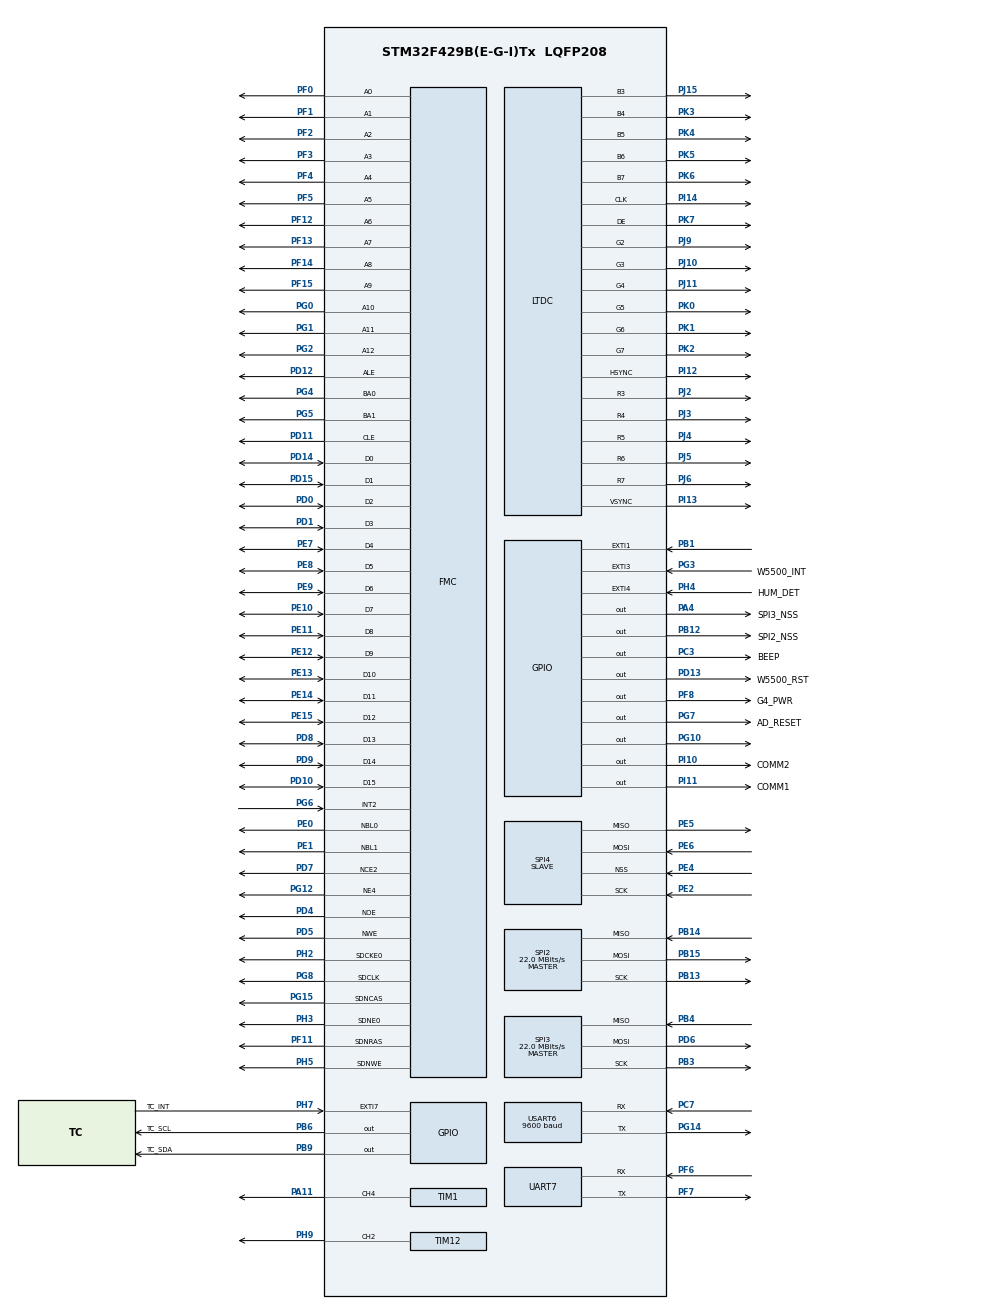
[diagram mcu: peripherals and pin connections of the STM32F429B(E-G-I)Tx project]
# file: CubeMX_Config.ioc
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DMA2D.ColorMode=DMA2D_OUTPUT_RGB565
Dma.MEMTOMEM.0.Direction=DMA_MEMORY_TO_MEMORY
Dma.MEMTOMEM.0.FIFOMode=DMA_FIFOMODE_ENABLE
Dma.MEMTOMEM.0.FIFOThreshold=DMA_FIFO_THRESHOLD_FULL
Dma.MEMTOMEM.0.Instance=DMA2_Stream0
Dma.MEMTOMEM.0.MemBurst=DMA_MBURST_INC8
Dma.MEMTOMEM.0.MemDataAlignment=DMA_MDATAALIGN_HALFWORD
Dma.MEMTOMEM.0.MemInc=DMA_MINC_ENABLE
Dma.MEMTOMEM.0.Mode=DMA_NORMAL
Dma.MEMTOMEM.0.PeriphBurst=DMA_PBURST_INC8
Dma.MEMTOMEM.0.PeriphDataAlignment=DMA_PDATAALIGN_HALFWORD
Dma.MEMTOMEM.0.PeriphInc=DMA_PINC_ENABLE
Dma.MEMTOMEM.0.Priority=DMA_PRIORITY_HIGH
Dma.Request0=MEMTOMEM
Dma.Request1=SPI4_RX
Dma.Request2=SPI4_TX
Dma.SPI4_RX.1.Direction=DMA_PERIPH_TO_MEMORY
Dma.SPI4_RX.1.FIFOMode=DMA_FIFOMODE_ENABLE
Dma.SPI4_RX.1.FIFOThreshold=DMA_FIFO_THRESHOLD_FULL
Dma.SPI4_RX.1.Instance=DMA2_Stream3
Dma.SPI4_RX.1.MemBurst=DMA_MBURST_SINGLE
Dma.SPI4_RX.1.MemDataAlignment=DMA_MDATAALIGN_BYTE
Dma.SPI4_RX.1.MemInc=DMA_MINC_ENABLE
Dma.SPI4_RX.1.Mode=DMA_NORMAL
Dma.SPI4_RX.1.PeriphBurst=DMA_PBURST_SINGLE
Dma.SPI4_RX.1.PeriphDataAlignment=DMA_PDATAALIGN_BYTE
Dma.SPI4_RX.1.PeriphInc=DMA_PINC_DISABLE
Dma.SPI4_RX.1.Priority=DMA_PRIORITY_VERY_HIGH
Dma.SPI4_TX.2.Direction=DMA_MEMORY_TO_PERIPH
Dma.SPI4_TX.2.FIFOMode=DMA_FIFOMODE_ENABLE
Dma.SPI4_TX.2.FIFOThreshold=DMA_FIFO_THRESHOLD_FULL
Dma.SPI4_TX.2.Instance=DMA2_Stream1
Dma.SPI4_TX.2.MemBurst=DMA_MBURST_SINGLE
Dma.SPI4_TX.2.MemDataAlignment=DMA_MDATAALIGN_BYTE
Dma.SPI4_TX.2.MemInc=DMA_MINC_ENABLE
Dma.SPI4_TX.2.Mode=DMA_NORMAL
Dma.SPI4_TX.2.PeriphBurst=DMA_PBURST_SINGLE
Dma.SPI4_TX.2.PeriphDataAlignment=DMA_PDATAALIGN_BYTE
Dma.SPI4_TX.2.PeriphInc=DMA_PINC_DISABLE
Dma.SPI4_TX.2.Priority=DMA_PRIORITY_VERY_HIGH
FMC.CASLatency1=FMC_SDRAM_CAS_LATENCY_3
FMC.ColumnBitsNumber1=FMC_SDRAM_COLUMN_BITS_NUM_9
FMC.ExitSelfRefreshDelay1=8
FMC.LoadToActiveDelay1=2
FMC.RCDDelay1=2
FMC.RPDelay1=2
FMC.ReadPipeDelay1=FMC_SDRAM_RPIPE_DELAY_1
FMC.RowCycleDelay1=8
FMC.SDClockPeriod1=FMC_SDRAM_CLOCK_PERIOD_2
FMC.SelfRefreshTime1=5
FMC.WriteRecoveryTime1=4
LTDC.ActiveW=800
LTDC.Alpha_L0=255
LTDC.BlendingFactor1_L0=LTDC_BLENDING_FACTOR1_PAxCA
LTDC.BlendingFactor2_L0=LTDC_BLENDING_FACTOR2_PAxCA
LTDC.FBStartAdress_L0=0xC0000000
LTDC.HBP=36
LTDC.HFP=211
LTDC.HSync=11
LTDC.ImageHeight_L0=480
LTDC.ImageWidth_L0=800
LTDC.Layers=0
LTDC.PCPolarity=LTDC_PCPOLARITY_IPC
LTDC.PixelFormat_L0=LTDC_PIXEL_FORMAT_RGB565
LTDC.VBP=24
LTDC.VFP=11
LTDC.VSync=2
LTDC.WindowX1_L0=799
LTDC.WindowY1_L0=479
Mcu.Family=STM32F4
Mcu.Name=STM32F429B(E-G-I)Tx
Mcu.Package=LQFP208
NVIC.DMA2D_IRQn=true\:0\:0\:false\:false\:true\:false\:true\:true\:true
NVIC.DMA2_Stream0_IRQn=true\:0\:0\:false\:false\:true\:false\:true\:true\:true
NVIC.DMA2_Stream1_IRQn=true\:0\:0\:false\:false\:true\:true\:false\:true\:true
NVIC.DMA2_Stream3_IRQn=true\:0\:0\:false\:false\:true\:true\:false\:true\:true
NVIC.EXTI1_IRQn=true\:0\:0\:false\:false\:true\:false\:true\:true\:true
NVIC.EXTI9_5_IRQn=true\:0\:0\:false\:false\:true\:false\:true\:true\:true
NVIC.FMC_IRQn=true\:0\:0\:false\:false\:true\:false\:true\:true\:true
NVIC.LTDC_IRQn=true\:0\:0\:false\:false\:true\:false\:true\:true\:true
NVIC.PriorityGroup=NVIC_PRIORITYGROUP_4
NVIC.SPI3_IRQn=true\:0\:0\:false\:false\:true\:false\:true\:true\:true
NVIC.SPI4_IRQn=true\:0\:0\:false\:false\:true\:false\:true\:true\:true
NVIC.TIM3_IRQn=true\:0\:0\:false\:false\:true\:false\:true\:true\:true
NVIC.UART7_IRQn=true\:0\:0\:false\:false\:true\:false\:true\:true\:true
NVIC.USART6_IRQn=true\:0\:0\:false\:false\:true\:false\:true\:true\:true
PA11.Signal=S_TIM1_CH4
PA13.Mode=Serial_Wire
PA13.Signal=SYS_JTMS-SWDIO
PA14.Mode=Serial_Wire
PA14.Signal=SYS_JTCK-SWCLK
PA4.GPIO_Label=SPI3_NSS
PA4.GPIO_Speed=GPIO_SPEED_FREQ_VERY_HIGH
PA4.PinState=GPIO_PIN_SET
PA4.Signal=GPIO_Output
PB1.GPIO_ModeDefaultEXTI=GPIO_MODE_IT_FALLING
PB1.Signal=GPXTI1
PB12.GPIO_Label=SPI2_NSS
PB12.GPIO_Speed=GPIO_SPEED_FREQ_VERY_HIGH
PB12.PinState=GPIO_PIN_SET
PB12.Signal=GPIO_Output
PB13.Mode=Full_Duplex_Master
PB13.Signal=SPI2_SCK
PB14.Mode=Full_Duplex_Master
PB14.Signal=SPI2_MISO
PB15.Mode=Full_Duplex_Master
PB15.Signal=SPI2_MOSI
PB3.Mode=Full_Duplex_Master
PB3.Signal=SPI3_SCK
PB4.Mode=Full_Duplex_Master
PB4.Signal=SPI3_MISO
PB6.GPIO_Label=TC_SCL
PB6.GPIO_ModeDefaultOutputPP=GPIO_MODE_OUTPUT_OD
PB6.GPIO_PuPd=GPIO_PULLUP
PB6.GPIO_Speed=GPIO_SPEED_FREQ_VERY_HIGH
PB6.PinState=GPIO_PIN_SET
PB6.Signal=GPIO_Output
PB9.GPIO_Label=TC_SDA
PB9.GPIO_ModeDefaultOutputPP=GPIO_MODE_OUTPUT_OD
PB9.GPIO_PuPd=GPIO_PULLUP
PB9.GPIO_Speed=GPIO_SPEED_FREQ_VERY_HIGH
PB9.PinState=GPIO_PIN_SET
PB9.Signal=GPIO_Output
PC14/OSC32_IN.Mode=LSE-External-Oscillator
PC14/OSC32_IN.Signal=RCC_OSC32_IN
PC15/OSC32_OUT.Mode=LSE-External-Oscillator
PC15/OSC32_OUT.Signal=RCC_OSC32_OUT
PC3.GPIO_Label=BEEP
PC3.GPIO_Speed=GPIO_SPEED_FREQ_VERY_HIGH
PC3.PinState=GPIO_PIN_RESET
PC3.Signal=GPIO_Output
PC6.GPIO_Label=AD_START
PC6.GPIO_Speed=GPIO_SPEED_FREQ_VERY_HIGH
PC6.Signal=S_TIM3_CH1
PC7.Mode=Asynchronous
PC7.Signal=USART6_RX
PD0.Signal=FMC_D2_DA2
PD1.Signal=FMC_D3_DA3
PD10.Signal=FMC_D15_DA15
PD11.Signal=FMC_A16_CLE
PD12.Signal=FMC_A17_ALE
PD13.GPIO_Label=W5500_RST
PD13.GPIO_Speed=GPIO_SPEED_FREQ_VERY_HIGH
PD13.PinState=GPIO_PIN_SET
PD13.Signal=GPIO_Output
PD14.Signal=FMC_D0_DA0
PD15.Signal=FMC_D1_DA1
PD4.Signal=FMC_NOE
PD5.Signal=FMC_NWE
PD6.Mode=Full_Duplex_Master
PD6.Signal=SPI3_MOSI
PD7.Mode=NandChipSelect2_1
PD7.Signal=FMC_NCE2
PD8.Signal=FMC_D13_DA13
PD9.Signal=FMC_D14_DA14
PE0.Signal=FMC_NBL0
PE1.Signal=FMC_NBL1
PE10.Signal=FMC_D7_DA7
PE11.Signal=FMC_D8_DA8
PE12.Signal=FMC_D9_DA9
PE13.Signal=FMC_D10_DA10
PE14.Signal=FMC_D11_DA11
PE15.Signal=FMC_D12_DA12
PE2.Mode=Full_Duplex_Slave
PE2.Signal=SPI4_SCK
PE4.Mode=NSS_Signal_Hard_Input
PE4.Signal=SPI4_NSS
PE5.Mode=Full_Duplex_Slave
PE5.Signal=SPI4_MISO
PE6.Mode=Full_Duplex_Slave
PE6.Signal=SPI4_MOSI
PE7.Signal=FMC_D4_DA4
PE8.Signal=FMC_D5_DA5
PE9.Signal=FMC_D6_DA6
PF0.Signal=FMC_A0
PF1.Signal=FMC_A1
PF11.Signal=FMC_SDNRAS
PF12.Signal=FMC_A6
PF13.Signal=FMC_A7
PF14.Signal=FMC_A8
PF15.Signal=FMC_A9
PF2.Signal=FMC_A2
PF3.Signal=FMC_A3
PF4.Signal=FMC_A4
PF5.Signal=FMC_A5
PF6.Mode=Asynchronous
PF6.Signal=UART7_RX
PF7.Mode=Asynchronous
PF7.Signal=UART7_TX
PF8.GPIO_Label=G4_PWR
PF8.Signal=GPIO_Output
PG0.Signal=FMC_A10
PG1.Signal=FMC_A11
PG10.GPIO_ModeDefaultOutputPP=GPIO_MODE_OUTPUT_PP
PG10.GPIO_Speed=GPIO_SPEED_FREQ_VERY_HIGH
PG10.PinState=GPIO_PIN_SET
PG10.Signal=GPIO_Output
PG12.Mode=NorPsramChipSelect4_1
PG12.Signal=FMC_NE4
PG14.Mode=Asynchronous
PG14.Signal=USART6_TX
PG15.Signal=FMC_SDNCAS
PG2.Signal=FMC_A12
PG3.GPIO_Label=W5500_INT
PG3.GPIO_ModeDefaultEXTI=GPIO_MODE_IT_FALLING
PG3.GPIO_PuPd=GPIO_PULLUP
PG3.Signal=GPXTI3
PG4.Signal=FMC_A14_BA0
PG5.Signal=FMC_A15_BA1
PG6.Signal=FMC_INT2
PG7.GPIO_Label=AD_RESET
PG7.GPIO_Speed=GPIO_SPEED_FREQ_VERY_HIGH
PG7.Signal=GPIO_Output
PG8.Signal=FMC_SDCLK
PH0/OSC_IN.Mode=HSE-External-Oscillator
PH0/OSC_IN.Signal=RCC_OSC_IN
PH1/OSC_OUT.Mode=HSE-External-Oscillator
PH1/OSC_OUT.Signal=RCC_OSC_OUT
PH2.Mode=SdramChipSelect1_1
PH2.Signal=FMC_SDCKE0
PH3.Mode=SdramChipSelect1_1
PH3.Signal=FMC_SDNE0
PH4.GPIO_Label=HUM_DET
PH4.Signal=GPXTI4
PH5.Signal=FMC_SDNWE
PH7.GPIO_Label=TC_INT
PH7.GPIO_ModeDefaultEXTI=GPIO_MODE_IT_FALLING
PH7.Signal=GPXTI7
PH9.Signal=S_TIM12_CH2
PI10.GPIO_Label=COMM2
PI10.GPIO_ModeDefaultOutputPP=GPIO_MODE_OUTPUT_OD
PI10.GPIO_PuPd=GPIO_PULLUP
PI10.GPIO_Speed=GPIO_SPEED_FREQ_VERY_HIGH
PI10.PinState=GPIO_PIN_SET
PI10.Signal=GPIO_Output
PI11.GPIO_Label=COMM1
PI11.GPIO_ModeDefaultOutputPP=GPIO_MODE_OUTPUT_OD
PI11.GPIO_PuPd=GPIO_PULLUP
PI11.GPIO_Speed=GPIO_SPEED_FREQ_VERY_HIGH
PI11.PinState=GPIO_PIN_SET
PI11.Signal=GPIO_Output
PI12.GPIO_Speed=GPIO_SPEED_FREQ_VERY_HIGH
PI12.Mode=RGB565
PI12.Signal=LTDC_HSYNC
PI13.GPIO_Speed=GPIO_SPEED_FREQ_VERY_HIGH
PI13.Mode=RGB565
PI13.Signal=LTDC_VSYNC
PI14.GPIO_Speed=GPIO_SPEED_FREQ_VERY_HIGH
PI14.Mode=RGB565
PI14.Signal=LTDC_CLK
PJ10.GPIO_Speed=GPIO_SPEED_FREQ_VERY_HIGH
PJ10.Mode=RGB565
PJ10.Signal=LTDC_G3
PJ11.GPIO_Speed=GPIO_SPEED_FREQ_VERY_HIGH
PJ11.Mode=RGB565
PJ11.Signal=LTDC_G4
PJ15.GPIO_Speed=GPIO_SPEED_FREQ_VERY_HIGH
PJ15.Mode=RGB565
PJ15.Signal=LTDC_B3
PJ2.GPIO_Speed=GPIO_SPEED_FREQ_VERY_HIGH
PJ2.Mode=RGB565
PJ2.Signal=LTDC_R3
PJ3.GPIO_Speed=GPIO_SPEED_FREQ_VERY_HIGH
PJ3.Mode=RGB565
PJ3.Signal=LTDC_R4
PJ4.GPIO_Speed=GPIO_SPEED_FREQ_VERY_HIGH
PJ4.Mode=RGB565
PJ4.Signal=LTDC_R5
PJ5.GPIO_Speed=GPIO_SPEED_FREQ_VERY_HIGH
PJ5.Mode=RGB565
PJ5.Signal=LTDC_R6
PJ6.GPIO_Speed=GPIO_SPEED_FREQ_VERY_HIGH
PJ6.Mode=RGB565
PJ6.Signal=LTDC_R7
PJ9.GPIO_Speed=GPIO_SPEED_FREQ_VERY_HIGH
PJ9.Mode=RGB565
PJ9.Signal=LTDC_G2
PK0.GPIO_Speed=GPIO_SPEED_FREQ_VERY_HIGH
PK0.Mode=RGB565
PK0.Signal=LTDC_G5
PK1.GPIO_Speed=GPIO_SPEED_FREQ_VERY_HIGH
PK1.Mode=RGB565
PK1.Signal=LTDC_G6
PK2.GPIO_Speed=GPIO_SPEED_FREQ_VERY_HIGH
PK2.Mode=RGB565
PK2.Signal=LTDC_G7
PK3.GPIO_Speed=GPIO_SPEED_FREQ_VERY_HIGH
PK3.Mode=RGB565
PK3.Signal=LTDC_B4
PK4.GPIO_Speed=GPIO_SPEED_FREQ_VERY_HIGH
PK4.Mode=RGB565
PK4.Signal=LTDC_B5
PK5.GPIO_Speed=GPIO_SPEED_FREQ_VERY_HIGH
PK5.Mode=RGB565
PK5.Signal=LTDC_B6
PK6.GPIO_Speed=GPIO_SPEED_FREQ_VERY_HIGH
PK6.Mode=RGB565
PK6.Signal=LTDC_B7
PK7.GPIO_Speed=GPIO_SPEED_FREQ_VERY_HIGH
PK7.Mode=RGB565
PK7.Signal=LTDC_DE
ProjectManager.HeapSize=0x2000
ProjectManager.StackSize=0x4000
ProjectManager.TargetToolchain=MDK-ARM V5.32
RCC.48MHZClocksFreq_Value=44000000
RCC.AHBFreq_Value=176000000
RCC.APB1CLKDivider=RCC_HCLK_DIV4
RCC.APB1Freq_Value=44000000
RCC.APB1TimFreq_Value=88000000
RCC.APB2CLKDivider=RCC_HCLK_DIV2
RCC.APB2Freq_Value=88000000
RCC.APB2TimFreq_Value=176000000
RCC.CortexFreq_Value=176000000
RCC.HCLKFreq_Value=176000000
RCC.HSE_VALUE=8000000
RCC.HSI_VALUE=16000000
RCC.PLLM=4
RCC.PLLN=176
RCC.PLLQ=8
RCC.PLLSAIN=50
RCC.PLLSourceVirtual=RCC_PLLSOURCE_HSE
RCC.RCC_RTC_Clock_Source=RCC_RTCCLKSOURCE_LSE
RCC.RCC_RTC_Clock_SourceVirtual=RCC_RTCCLKSOURCE_LSE
RCC.SYSCLKFreq_VALUE=176000000
RCC.SYSCLKSource=RCC_SYSCLKSOURCE_PLLCLK
RCC.VCOOutputFreq_Value=352000000
RealThread.RT-Thread.3.1.3.FINSH_THREAD_STACK_SIZE=2048
RealThread.RT-Thread.3.1.3.RTAaThreadCcRTOSJjkernel=true
RealThread.RT-Thread.3.1.3.RTAaThreadCcRTOSJjshell=true
RealThread.RT-Thread.3.1.3.RT_DEBUG=1
RealThread.RT-Thread.3.1.3.RT_MAIN_THREAD_STACK_SIZE=8192
RealThread.RT-Thread.3.1.3.RT_USING_EVENT=1
RealThread.RT-Thread.3.1.3.RT_USING_HEAP=1
RealThread.RT-Thread.3.1.3.RT_USING_MAILBOX=1
RealThread.RT-Thread.3.1.3.RT_USING_MESSAGEQUEUE=1
RealThread.RT-Thread.3.1.3.RT_USING_MUTEX=1
RealThread.RT-Thread.3.1.3.RT_USING_OVERFLOW_CHECK=1
SH.FMC_A0.0=FMC_A0,4b-a1
SH.FMC_A0.1=FMC_A0,13b-sda1
SH.FMC_A1.0=FMC_A1,4b-a1
SH.FMC_A1.1=FMC_A1,13b-sda1
SH.FMC_A10.0=FMC_A10,13b-sda1
SH.FMC_A11.0=FMC_A11,13b-sda1
SH.FMC_A12.0=FMC_A12,13b-sda1
SH.FMC_A14_BA0.0=FMC_BA0,FourSdramBanks1
SH.FMC_A15_BA1.0=FMC_BA1,FourSdramBanks1
SH.FMC_A16_CLE.0=FMC_CLE,8b-dmux1
SH.FMC_A17_ALE.0=FMC_ALE,8b-dmux1
SH.FMC_A2.0=FMC_A2,4b-a1
SH.FMC_A2.1=FMC_A2,13b-sda1
SH.FMC_A3.0=FMC_A3,4b-a1
SH.FMC_A3.1=FMC_A3,13b-sda1
SH.FMC_A4.0=FMC_A4,13b-sda1
SH.FMC_A5.0=FMC_A5,13b-sda1
SH.FMC_A6.0=FMC_A6,13b-sda1
SH.FMC_A7.0=FMC_A7,13b-sda1
SH.FMC_A8.0=FMC_A8,13b-sda1
SH.FMC_A9.0=FMC_A9,13b-sda1
SH.FMC_D0_DA0.0=FMC_D0,8b-dmux1
SH.FMC_D0_DA0.1=FMC_D0,sd-16b-d1
SH.FMC_D0_DA0.2=FMC_D0,16b-d1
SH.FMC_D10_DA10.0=FMC_D10,sd-16b-d1
SH.FMC_D10_DA10.1=FMC_D10,16b-d1
SH.FMC_D11_DA11.0=FMC_D11,sd-16b-d1
SH.FMC_D11_DA11.1=FMC_D11,16b-d1
SH.FMC_D12_DA12.0=FMC_D12,sd-16b-d1
SH.FMC_D12_DA12.1=FMC_D12,16b-d1
SH.FMC_D13_DA13.0=FMC_D13,sd-16b-d1
SH.FMC_D13_DA13.1=FMC_D13,16b-d1
SH.FMC_D14_DA14.0=FMC_D14,sd-16b-d1
SH.FMC_D14_DA14.1=FMC_D14,16b-d1
SH.FMC_D15_DA15.0=FMC_D15,sd-16b-d1
SH.FMC_D15_DA15.1=FMC_D15,16b-d1
SH.FMC_D1_DA1.0=FMC_D1,8b-dmux1
SH.FMC_D1_DA1.1=FMC_D1,sd-16b-d1
SH.FMC_D1_DA1.2=FMC_D1,16b-d1
SH.FMC_D2_DA2.0=FMC_D2,8b-dmux1
SH.FMC_D2_DA2.1=FMC_D2,sd-16b-d1
SH.FMC_D2_DA2.2=FMC_D2,16b-d1
SH.FMC_D3_DA3.0=FMC_D3,8b-dmux1
SH.FMC_D3_DA3.1=FMC_D3,sd-16b-d1
SH.FMC_D3_DA3.2=FMC_D3,16b-d1
SH.FMC_D4_DA4.0=FMC_D4,8b-dmux1
SH.FMC_D4_DA4.1=FMC_D4,sd-16b-d1
SH.FMC_D4_DA4.2=FMC_D4,16b-d1
SH.FMC_D5_DA5.0=FMC_D5,8b-dmux1
SH.FMC_D5_DA5.1=FMC_D5,sd-16b-d1
SH.FMC_D5_DA5.2=FMC_D5,16b-d1
SH.FMC_D6_DA6.0=FMC_D6,8b-dmux1
SH.FMC_D6_DA6.1=FMC_D6,sd-16b-d1
SH.FMC_D6_DA6.2=FMC_D6,16b-d1
SH.FMC_D7_DA7.0=FMC_D7,8b-dmux1
SH.FMC_D7_DA7.1=FMC_D7,sd-16b-d1
SH.FMC_D7_DA7.2=FMC_D7,16b-d1
SH.FMC_D8_DA8.0=FMC_D8,sd-16b-d1
SH.FMC_D8_DA8.1=FMC_D8,16b-d1
SH.FMC_D9_DA9.0=FMC_D9,sd-16b-d1
SH.FMC_D9_DA9.1=FMC_D9,16b-d1
SH.FMC_INT2.0=FMC_INT2,Interrupt21
SH.FMC_NBL0.0=FMC_NBL0,Sd2ByteEnable1
SH.FMC_NBL1.0=FMC_NBL1,Sd2ByteEnable1
SH.FMC_NOE.0=FMC_NOE,8b-dmux1
SH.FMC_NOE.1=FMC_NOE,Sram1
SH.FMC_NWE.0=FMC_NWE,8b-dmux1
SH.FMC_NWE.1=FMC_NWE,Sram1
SH.FMC_SDCLK.0=FMC_SDCLK,13b-sda1
SH.FMC_SDNCAS.0=FMC_SDNCAS,13b-sda1
SH.FMC_SDNRAS.0=FMC_SDNRAS,13b-sda1
SH.FMC_SDNWE.0=FMC_SDNWE,13b-sda1
SH.S_TIM12_CH2.0=TIM12_CH2,PWM Generation2 CH2
SH.S_TIM1_CH4.0=TIM1_CH4,PWM Generation4 CH4
SH.S_TIM3_CH1.0=TIM3_CH1
SPI2.CalculateBaudRate=22.0 MBits/s
SPI2.Direction=SPI_DIRECTION_2LINES
SPI2.Mode=SPI_MODE_MASTER
SPI2.VirtualType=VM_MASTER
SPI3.BaudRatePrescaler=SPI_BAUDRATEPRESCALER_2
SPI3.CalculateBaudRate=22.0 MBits/s
SPI3.Direction=SPI_DIRECTION_2LINES
SPI3.Mode=SPI_MODE_MASTER
SPI3.VirtualType=VM_MASTER
SPI4.Direction=SPI_DIRECTION_2LINES
SPI4.Mode=SPI_MODE_SLAVE
SPI4.VirtualNSS=VM_NSSHARD
SPI4.VirtualType=VM_SLAVE
TIM1.AutoReloadPreload=TIM_AUTORELOAD_PRELOAD_ENABLE
TIM1.Channel-PWM\ Generation4\ CH4=TIM_CHANNEL_4
TIM1.Period=4499
TIM1.Pulse-PWM\ Generation4\ CH4=2249
TIM12.Channel-PWM\ Generation2\ CH2=TIM_CHANNEL_2
TIM3.AutoReloadPreload=TIM_AUTORELOAD_PRELOAD_ENABLE
TIM3.Period=9374
TIM3.Prescaler=0
UART7.VirtualMode=Asynchronous
USART6.BaudRate=9600
USART6.VirtualMode=VM_ASYNC
VP_DMA2D_VS_DMA2D.Mode=DMA2D_Activate
VP_RTC_VS_RTC_Activate.Mode=RTC_Enabled
VP_RealThread.RT-Thread_VS_RTOSJjRTAaThread_3.1.3.Mode=RTOSJjRTAaThread
VP_TIM12_VS_ClockSourceINT.Mode=Internal
VP_TIM1_VS_ClockSourceINT.Mode=Internal
VP_TIM3_VS_ClockSourceINT.Mode=Internal
board=custom

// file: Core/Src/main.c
/* USER CODE BEGIN Header */
/**
  ******************************************************************************
  * @file           : main.c
  * @brief          : Main program body
  ******************************************************************************
  * @attention
  *
  * Copyright (c) 2025 STMicroelectronics.
  * All rights reserved.
  *
  * This software is licensed under terms that can be found in the LICENSE file
  * in the root directory of this software component.
  * If no LICENSE file comes with this software, it is provided AS-IS.
  *
  ******************************************************************************
  */
/* USER CODE END Header */
#include "main.h"

DMA2D_HandleTypeDef hdma2d;

LTDC_HandleTypeDef hltdc;

RTC_HandleTypeDef hrtc;

SPI_HandleTypeDef hspi2;
SPI_HandleTypeDef hspi3;
SPI_HandleTypeDef hspi4;
DMA_HandleTypeDef hdma_spi4_rx;
DMA_HandleTypeDef hdma_spi4_tx;

TIM_HandleTypeDef htim1;
TIM_HandleTypeDef htim3;
TIM_HandleTypeDef htim12;

UART_HandleTypeDef huart7;
UART_HandleTypeDef huart6;

DMA_HandleTypeDef hdma_memtomem_dma2_stream0;
SRAM_HandleTypeDef hsram1;
NAND_HandleTypeDef hnand1;
SDRAM_HandleTypeDef hsdram1;

void SystemClock_Config(void);
static void MX_GPIO_Init(void);
static void MX_DMA_Init(void);
static void MX_FMC_Init(void);
static void MX_SPI3_Init(void);
static void MX_SPI4_Init(void);
static void MX_RTC_Init(void);
static void MX_TIM3_Init(void);
static void MX_DMA2D_Init(void);
static void MX_LTDC_Init(void);
static void MX_TIM1_Init(void);
static void MX_SPI2_Init(void);
static void MX_UART7_Init(void);
static void MX_USART6_UART_Init(void);
static void MX_TIM12_Init(void);

int main(void)
{

  /* MCU Configuration--------------------------------------------------------*/

  /* Reset of all peripherals, Initializes the Flash interface and the Systick. */
  HAL_Init();

  /* Configure the system clock */
  SystemClock_Config();

  /* Initialize all configured peripherals */
  MX_GPIO_Init();
  MX_DMA_Init();
  MX_FMC_Init();
  MX_SPI3_Init();
  MX_SPI4_Init();
  MX_RTC_Init();
  MX_TIM3_Init();
  MX_DMA2D_Init();
  MX_LTDC_Init();
  MX_TIM1_Init();
  MX_SPI2_Init();
  MX_UART7_Init();
  MX_USART6_UART_Init();
  MX_TIM12_Init();

  /* Infinite loop */
  while (1)
  {

  }
}

void SystemClock_Config(void)
{
  RCC_OscInitTypeDef RCC_OscInitStruct = {0};
  RCC_ClkInitTypeDef RCC_ClkInitStruct = {0};

  /** Configure the main internal regulator output voltage
  */
  __HAL_RCC_PWR_CLK_ENABLE();
  __HAL_PWR_VOLTAGESCALING_CONFIG(PWR_REGULATOR_VOLTAGE_SCALE1);

  /** Initializes the RCC Oscillators according to the specified parameters
  * in the RCC_OscInitTypeDef structure.
  */
  RCC_OscInitStruct.OscillatorType = RCC_OSCILLATORTYPE_HSE|RCC_OSCILLATORTYPE_LSE;
  RCC_OscInitStruct.HSEState = RCC_HSE_ON;
  RCC_OscInitStruct.LSEState = RCC_LSE_ON;
  RCC_OscInitStruct.PLL.PLLState = RCC_PLL_ON;
  RCC_OscInitStruct.PLL.PLLSource = RCC_PLLSOURCE_HSE;
  RCC_OscInitStruct.PLL.PLLM = 4;
  RCC_OscInitStruct.PLL.PLLN = 180;
  RCC_OscInitStruct.PLL.PLLP = RCC_PLLP_DIV2;
  RCC_OscInitStruct.PLL.PLLQ = 8;
  if (HAL_RCC_OscConfig(&RCC_OscInitStruct) != HAL_OK)
  {
    Error_Handler();
  }

  /** Activate the Over-Drive mode
  */
  if (HAL_PWREx_EnableOverDrive() != HAL_OK)
  {
    Error_Handler();
  }

  /** Initializes the CPU, AHB and APB buses clocks
  */
  RCC_ClkInitStruct.ClockType = RCC_CLOCKTYPE_HCLK|RCC_CLOCKTYPE_SYSCLK
                              |RCC_CLOCKTYPE_PCLK1|RCC_CLOCKTYPE_PCLK2;
  RCC_ClkInitStruct.SYSCLKSource = RCC_SYSCLKSOURCE_PLLCLK;
  RCC_ClkInitStruct.AHBCLKDivider = RCC_SYSCLK_DIV1;
  RCC_ClkInitStruct.APB1CLKDivider = RCC_HCLK_DIV4;
  RCC_ClkInitStruct.APB2CLKDivider = RCC_HCLK_DIV2;

  if (HAL_RCC_ClockConfig(&RCC_ClkInitStruct, FLASH_LATENCY_5) != HAL_OK)
  {
    Error_Handler();
  }
}

static void MX_DMA2D_Init(void)
{

  hdma2d.Instance = DMA2D;
  hdma2d.Init.Mode = DMA2D_M2M;
  hdma2d.Init.ColorMode = DMA2D_OUTPUT_RGB565;
  hdma2d.Init.OutputOffset = 0;
  hdma2d.LayerCfg[1].InputOffset = 0;
  hdma2d.LayerCfg[1].InputColorMode = DMA2D_INPUT_RGB565;
  hdma2d.LayerCfg[1].AlphaMode = DMA2D_NO_MODIF_ALPHA;
  hdma2d.LayerCfg[1].InputAlpha = 0;
  if (HAL_DMA2D_Init(&hdma2d) != HAL_OK)
  {
    Error_Handler();
  }
  if (HAL_DMA2D_ConfigLayer(&hdma2d, 1) != HAL_OK)
  {
    Error_Handler();
  }

}

static void MX_LTDC_Init(void)
{

  LTDC_LayerCfgTypeDef pLayerCfg = {0};

  hltdc.Instance = LTDC;
  hltdc.Init.HSPolarity = LTDC_HSPOLARITY_AL;
  hltdc.Init.VSPolarity = LTDC_VSPOLARITY_AL;
  hltdc.Init.DEPolarity = LTDC_DEPOLARITY_AL;
  hltdc.Init.PCPolarity = LTDC_PCPOLARITY_IPC;
  hltdc.Init.HorizontalSync = 10;
  hltdc.Init.VerticalSync = 1;
  hltdc.Init.AccumulatedHBP = 46;
  hltdc.Init.AccumulatedVBP = 25;
  hltdc.Init.AccumulatedActiveW = 846;
  hltdc.Init.AccumulatedActiveH = 505;
  hltdc.Init.TotalWidth = 1057;
  hltdc.Init.TotalHeigh = 516;
  hltdc.Init.Backcolor.Blue = 0;
  hltdc.Init.Backcolor.Green = 0;
  hltdc.Init.Backcolor.Red = 0;
  if (HAL_LTDC_Init(&hltdc) != HAL_OK)
  {
    Error_Handler();
  }
  pLayerCfg.WindowX0 = 0;
  pLayerCfg.WindowX1 = 799;
  pLayerCfg.WindowY0 = 0;
  pLayerCfg.WindowY1 = 479;
  pLayerCfg.PixelFormat = LTDC_PIXEL_FORMAT_RGB565;
  pLayerCfg.Alpha = 255;
  pLayerCfg.Alpha0 = 0;
  pLayerCfg.BlendingFactor1 = LTDC_BLENDING_FACTOR1_PAxCA;
  pLayerCfg.BlendingFactor2 = LTDC_BLENDING_FACTOR2_PAxCA;
  pLayerCfg.FBStartAdress = 0xC0000000;
  pLayerCfg.ImageWidth = 800;
  pLayerCfg.ImageHeight = 480;
  pLayerCfg.Backcolor.Blue = 0;
  pLayerCfg.Backcolor.Green = 0;
  pLayerCfg.Backcolor.Red = 0;
  if (HAL_LTDC_ConfigLayer(&hltdc, &pLayerCfg, 0) != HAL_OK)
  {
    Error_Handler();
  }

}

static void MX_RTC_Init(void)
{

  /** Initialize RTC Only
  */
  hrtc.Instance = RTC;
  hrtc.Init.HourFormat = RTC_HOURFORMAT_24;
  hrtc.Init.AsynchPrediv = 127;
  hrtc.Init.SynchPrediv = 255;
  hrtc.Init.OutPut = RTC_OUTPUT_DISABLE;
  hrtc.Init.OutPutPolarity = RTC_OUTPUT_POLARITY_HIGH;
  hrtc.Init.OutPutType = RTC_OUTPUT_TYPE_OPENDRAIN;
  if (HAL_RTC_Init(&hrtc) != HAL_OK)
  {
    Error_Handler();
  }

}

static void MX_SPI2_Init(void)
{

  /* SPI2 parameter configuration*/
  hspi2.Instance = SPI2;
  hspi2.Init.Mode = SPI_MODE_MASTER;
  hspi2.Init.Direction = SPI_DIRECTION_2LINES;
  hspi2.Init.DataSize = SPI_DATASIZE_8BIT;
  hspi2.Init.CLKPolarity = SPI_POLARITY_LOW;
  hspi2.Init.CLKPhase = SPI_PHASE_1EDGE;
  hspi2.Init.NSS = SPI_NSS_SOFT;
  hspi2.Init.BaudRatePrescaler = SPI_BAUDRATEPRESCALER_2;
  hspi2.Init.FirstBit = SPI_FIRSTBIT_MSB;
  hspi2.Init.TIMode = SPI_TIMODE_DISABLE;
  hspi2.Init.CRCCalculation = SPI_CRCCALCULATION_DISABLE;
  hspi2.Init.CRCPolynomial = 10;
  if (HAL_SPI_Init(&hspi2) != HAL_OK)
  {
    Error_Handler();
  }

}

static void MX_SPI3_Init(void)
{

  /* SPI3 parameter configuration*/
  hspi3.Instance = SPI3;
  hspi3.Init.Mode = SPI_MODE_MASTER;
  hspi3.Init.Direction = SPI_DIRECTION_2LINES;
  hspi3.Init.DataSize = SPI_DATASIZE_8BIT;
  hspi3.Init.CLKPolarity = SPI_POLARITY_LOW;
  hspi3.Init.CLKPhase = SPI_PHASE_1EDGE;
  hspi3.Init.NSS = SPI_NSS_SOFT;
  hspi3.Init.BaudRatePrescaler = SPI_BAUDRATEPRESCALER_2;
  hspi3.Init.FirstBit = SPI_FIRSTBIT_MSB;
  hspi3.Init.TIMode = SPI_TIMODE_DISABLE;
  hspi3.Init.CRCCalculation = SPI_CRCCALCULATION_DISABLE;
  hspi3.Init.CRCPolynomial = 10;
  if (HAL_SPI_Init(&hspi3) != HAL_OK)
  {
    Error_Handler();
  }

}

static void MX_SPI4_Init(void)
{

  /* SPI4 parameter configuration*/
  hspi4.Instance = SPI4;
  hspi4.Init.Mode = SPI_MODE_SLAVE;
  hspi4.Init.Direction = SPI_DIRECTION_2LINES;
  hspi4.Init.DataSize = SPI_DATASIZE_8BIT;
  hspi4.Init.CLKPolarity = SPI_POLARITY_LOW;
  hspi4.Init.CLKPhase = SPI_PHASE_1EDGE;
  hspi4.Init.NSS = SPI_NSS_HARD_INPUT;
  hspi4.Init.FirstBit = SPI_FIRSTBIT_MSB;
  hspi4.Init.TIMode = SPI_TIMODE_DISABLE;
  hspi4.Init.CRCCalculation = SPI_CRCCALCULATION_DISABLE;
  hspi4.Init.CRCPolynomial = 10;
  if (HAL_SPI_Init(&hspi4) != HAL_OK)
  {
    Error_Handler();
  }

}

static void MX_TIM1_Init(void)
{

  TIM_ClockConfigTypeDef sClockSourceConfig = {0};
  TIM_MasterConfigTypeDef sMasterConfig = {0};
  TIM_OC_InitTypeDef sConfigOC = {0};
  TIM_BreakDeadTimeConfigTypeDef sBreakDeadTimeConfig = {0};

  htim1.Instance = TIM1;
  htim1.Init.Prescaler = 0;
  htim1.Init.CounterMode = TIM_COUNTERMODE_UP;
  htim1.Init.Period = 4499;
  htim1.Init.ClockDivision = TIM_CLOCKDIVISION_DIV1;
  htim1.Init.RepetitionCounter = 0;
  htim1.Init.AutoReloadPreload = TIM_AUTORELOAD_PRELOAD_ENABLE;
  if (HAL_TIM_Base_Init(&htim1) != HAL_OK)
  {
    Error_Handler();
  }
  sClockSourceConfig.ClockSource = TIM_CLOCKSOURCE_INTERNAL;
  if (HAL_TIM_ConfigClockSource(&htim1, &sClockSourceConfig) != HAL_OK)
  {
    Error_Handler();
  }
  if (HAL_TIM_PWM_Init(&htim1) != HAL_OK)
  {
    Error_Handler();
  }
  sMasterConfig.MasterOutputTrigger = TIM_TRGO_RESET;
  sMasterConfig.MasterSlaveMode = TIM_MASTERSLAVEMODE_DISABLE;
  if (HAL_TIMEx_MasterConfigSynchronization(&htim1, &sMasterConfig) != HAL_OK)
  {
    Error_Handler();
  }
  sConfigOC.OCMode = TIM_OCMODE_PWM1;
  sConfigOC.Pulse = 2249;
  sConfigOC.OCPolarity = TIM_OCPOLARITY_HIGH;
  sConfigOC.OCFastMode = TIM_OCFAST_DISABLE;
  sConfigOC.OCIdleState = TIM_OCIDLESTATE_RESET;
  sConfigOC.OCNIdleState = TIM_OCNIDLESTATE_RESET;
  if (HAL_TIM_PWM_ConfigChannel(&htim1, &sConfigOC, TIM_CHANNEL_4) != HAL_OK)
  {
    Error_Handler();
  }
  sBreakDeadTimeConfig.OffStateRunMode = TIM_OSSR_DISABLE;
  sBreakDeadTimeConfig.OffStateIDLEMode = TIM_OSSI_DISABLE;
  sBreakDeadTimeConfig.LockLevel = TIM_LOCKLEVEL_OFF;
  sBreakDeadTimeConfig.DeadTime = 0;
  sBreakDeadTimeConfig.BreakState = TIM_BREAK_DISABLE;
  sBreakDeadTimeConfig.BreakPolarity = TIM_BREAKPOLARITY_HIGH;
  sBreakDeadTimeConfig.AutomaticOutput = TIM_AUTOMATICOUTPUT_DISABLE;
  if (HAL_TIMEx_ConfigBreakDeadTime(&htim1, &sBreakDeadTimeConfig) != HAL_OK)
  {
    Error_Handler();
  }
  HAL_TIM_MspPostInit(&htim1);

}

static void MX_TIM3_Init(void)
{

  TIM_ClockConfigTypeDef sClockSourceConfig = {0};
  TIM_MasterConfigTypeDef sMasterConfig = {0};

  htim3.Instance = TIM3;
  htim3.Init.Prescaler = 0;
  htim3.Init.CounterMode = TIM_COUNTERMODE_UP;
  htim3.Init.Period = 9374;
  htim3.Init.ClockDivision = TIM_CLOCKDIVISION_DIV1;
  htim3.Init.AutoReloadPreload = TIM_AUTORELOAD_PRELOAD_ENABLE;
  if (HAL_TIM_Base_Init(&htim3) != HAL_OK)
  {
    Error_Handler();
  }
  sClockSourceConfig.ClockSource = TIM_CLOCKSOURCE_INTERNAL;
  if (HAL_TIM_ConfigClockSource(&htim3, &sClockSourceConfig) != HAL_OK)
  {
    Error_Handler();
  }
  sMasterConfig.MasterOutputTrigger = TIM_TRGO_RESET;
  sMasterConfig.MasterSlaveMode = TIM_MASTERSLAVEMODE_DISABLE;
  if (HAL_TIMEx_MasterConfigSynchronization(&htim3, &sMasterConfig) != HAL_OK)
  {
    Error_Handler();
  }

}

static void MX_TIM12_Init(void)
{

  TIM_ClockConfigTypeDef sClockSourceConfig = {0};
  TIM_OC_InitTypeDef sConfigOC = {0};

  htim12.Instance = TIM12;
  htim12.Init.Prescaler = 0;
  htim12.Init.CounterMode = TIM_COUNTERMODE_UP;
  htim12.Init.Period = 65535;
  htim12.Init.ClockDivision = TIM_CLOCKDIVISION_DIV1;
  htim12.Init.AutoReloadPreload = TIM_AUTORELOAD_PRELOAD_DISABLE;
  if (HAL_TIM_Base_Init(&htim12) != HAL_OK)
  {
    Error_Handler();
  }
  sClockSourceConfig.ClockSource = TIM_CLOCKSOURCE_INTERNAL;
  if (HAL_TIM_ConfigClockSource(&htim12, &sClockSourceConfig) != HAL_OK)
  {
    Error_Handler();
  }
  if (HAL_TIM_PWM_Init(&htim12) != HAL_OK)
  {
    Error_Handler();
  }
  sConfigOC.OCMode = TIM_OCMODE_PWM1;
  sConfigOC.Pulse = 0;
  sConfigOC.OCPolarity = TIM_OCPOLARITY_HIGH;
  sConfigOC.OCFastMode = TIM_OCFAST_DISABLE;
  if (HAL_TIM_PWM_ConfigChannel(&htim12, &sConfigOC, TIM_CHANNEL_2) != HAL_OK)
  {
    Error_Handler();
  }
  HAL_TIM_MspPostInit(&htim12);

}

static void MX_UART7_Init(void)
{

  huart7.Instance = UART7;
  huart7.Init.BaudRate = 115200;
  huart7.Init.WordLength = UART_WORDLENGTH_8B;
  huart7.Init.StopBits = UART_STOPBITS_1;
  huart7.Init.Parity = UART_PARITY_NONE;
  huart7.Init.Mode = UART_MODE_TX_RX;
  huart7.Init.HwFlowCtl = UART_HWCONTROL_NONE;
  huart7.Init.OverSampling = UART_OVERSAMPLING_16;
  if (HAL_UART_Init(&huart7) != HAL_OK)
  {
    Error_Handler();
  }

}

static void MX_USART6_UART_Init(void)
{

  huart6.Instance = USART6;
  huart6.Init.BaudRate = 9600;
  huart6.Init.WordLength = UART_WORDLENGTH_8B;
  huart6.Init.StopBits = UART_STOPBITS_1;
  huart6.Init.Parity = UART_PARITY_NONE;
  huart6.Init.Mode = UART_MODE_TX_RX;
  huart6.Init.HwFlowCtl = UART_HWCONTROL_NONE;
  huart6.Init.OverSampling = UART_OVERSAMPLING_16;
  if (HAL_UART_Init(&huart6) != HAL_OK)
  {
    Error_Handler();
  }

}

static void MX_DMA_Init(void)
{

  /* DMA controller clock enable */
  __HAL_RCC_DMA2_CLK_ENABLE();

  /* Configure DMA request hdma_memtomem_dma2_stream0 on DMA2_Stream0 */
  hdma_memtomem_dma2_stream0.Instance = DMA2_Stream0;
  hdma_memtomem_dma2_stream0.Init.Channel = DMA_CHANNEL_0;
  hdma_memtomem_dma2_stream0.Init.Direction = DMA_MEMORY_TO_MEMORY;
  hdma_memtomem_dma2_stream0.Init.PeriphInc = DMA_PINC_ENABLE;
  hdma_memtomem_dma2_stream0.Init.MemInc = DMA_MINC_ENABLE;
  hdma_memtomem_dma2_stream0.Init.PeriphDataAlignment = DMA_PDATAALIGN_HALFWORD;
  hdma_memtomem_dma2_stream0.Init.MemDataAlignment = DMA_MDATAALIGN_HALFWORD;
  hdma_memtomem_dma2_stream0.Init.Mode = DMA_NORMAL;
  hdma_memtomem_dma2_stream0.Init.Priority = DMA_PRIORITY_HIGH;
  hdma_memtomem_dma2_stream0.Init.FIFOMode = DMA_FIFOMODE_ENABLE;
  hdma_memtomem_dma2_stream0.Init.FIFOThreshold = DMA_FIFO_THRESHOLD_FULL;
  hdma_memtomem_dma2_stream0.Init.MemBurst = DMA_MBURST_INC8;
  hdma_memtomem_dma2_stream0.Init.PeriphBurst = DMA_PBURST_INC8;
  if (HAL_DMA_Init(&hdma_memtomem_dma2_stream0) != HAL_OK)
  {
    Error_Handler( );
  }

  /* DMA interrupt init */
  /* DMA2_Stream0_IRQn interrupt configuration */
  HAL_NVIC_SetPriority(DMA2_Stream0_IRQn, 0, 0);
  HAL_NVIC_EnableIRQ(DMA2_Stream0_IRQn);
  /* DMA2_Stream1_IRQn interrupt configuration */
  HAL_NVIC_SetPriority(DMA2_Stream1_IRQn, 0, 0);
  HAL_NVIC_EnableIRQ(DMA2_Stream1_IRQn);
  /* DMA2_Stream3_IRQn interrupt configuration */
  HAL_NVIC_SetPriority(DMA2_Stream3_IRQn, 0, 0);
  HAL_NVIC_EnableIRQ(DMA2_Stream3_IRQn);

}

/* FMC initialization function */
static void MX_FMC_Init(void)
{

  FMC_NORSRAM_TimingTypeDef Timing = {0};
  FMC_NAND_PCC_TimingTypeDef ComSpaceTiming = {0};
  FMC_NAND_PCC_TimingTypeDef AttSpaceTiming = {0};
  FMC_SDRAM_TimingTypeDef SdramTiming = {0};

  /** Perform the SRAM1 memory initialization sequence
  */
  hsram1.Instance = FMC_NORSRAM_DEVICE;
  hsram1.Extended = FMC_NORSRAM_EXTENDED_DEVICE;
  /* hsram1.Init */
  hsram1.Init.NSBank = FMC_NORSRAM_BANK4;
  hsram1.Init.DataAddressMux = FMC_DATA_ADDRESS_MUX_DISABLE;
  hsram1.Init.MemoryType = FMC_MEMORY_TYPE_SRAM;
  hsram1.Init.MemoryDataWidth = FMC_NORSRAM_MEM_BUS_WIDTH_16;
  hsram1.Init.BurstAccessMode = FMC_BURST_ACCESS_MODE_DISABLE;
  hsram1.Init.WaitSignalPolarity = FMC_WAIT_SIGNAL_POLARITY_LOW;
  hsram1.Init.WrapMode = FMC_WRAP_MODE_DISABLE;
  hsram1.Init.WaitSignalActive = FMC_WAIT_TIMING_BEFORE_WS;
  hsram1.Init.WriteOperation = FMC_WRITE_OPERATION_DISABLE;
  hsram1.Init.WaitSignal = FMC_WAIT_SIGNAL_DISABLE;
  hsram1.Init.ExtendedMode = FMC_EXTENDED_MODE_DISABLE;
  hsram1.Init.AsynchronousWait = FMC_ASYNCHRONOUS_WAIT_DISABLE;
  hsram1.Init.WriteBurst = FMC_WRITE_BURST_DISABLE;
  hsram1.Init.ContinuousClock = FMC_CONTINUOUS_CLOCK_SYNC_ONLY;
  hsram1.Init.PageSize = FMC_PAGE_SIZE_NONE;
  /* Timing */
  Timing.AddressSetupTime = 15;
  Timing.AddressHoldTime = 15;
  Timing.DataSetupTime = 255;
  Timing.BusTurnAroundDuration = 15;
  Timing.CLKDivision = 16;
  Timing.DataLatency = 17;
  Timing.AccessMode = FMC_ACCESS_MODE_A;
  /* ExtTiming */

  if (HAL_SRAM_Init(&hsram1, &Timing, NULL) != HAL_OK)
  {
    Error_Handler( );
  }

  /** Perform the NAND1 memory initialization sequence
  */
  hnand1.Instance = FMC_NAND_DEVICE;
  /* hnand1.Init */
  hnand1.Init.NandBank = FMC_NAND_BANK2;
  hnand1.Init.Waitfeature = FMC_NAND_PCC_WAIT_FEATURE_ENABLE;
  hnand1.Init.MemoryDataWidth = FMC_NAND_PCC_MEM_BUS_WIDTH_8;
  hnand1.Init.EccComputation = FMC_NAND_ECC_DISABLE;
  hnand1.Init.ECCPageSize = FMC_NAND_ECC_PAGE_SIZE_256BYTE;
  hnand1.Init.TCLRSetupTime = 0;
  hnand1.Init.TARSetupTime = 0;
  /* hnand1.Config */
  hnand1.Config.PageSize = 0;
  hnand1.Config.SpareAreaSize = 0;
  hnand1.Config.BlockSize = 0;
  hnand1.Config.BlockNbr = 0;
  hnand1.Config.PlaneNbr = 0;
  hnand1.Config.PlaneSize = 0;
  hnand1.Config.ExtraCommandEnable = DISABLE;
  /* ComSpaceTiming */
  ComSpaceTiming.SetupTime = 252;
  ComSpaceTiming.WaitSetupTime = 252;
  ComSpaceTiming.HoldSetupTime = 252;
  ComSpaceTiming.HiZSetupTime = 252;
  /* AttSpaceTiming */
  AttSpaceTiming.SetupTime = 252;
  AttSpaceTiming.WaitSetupTime = 252;
  AttSpaceTiming.HoldSetupTime = 252;
  AttSpaceTiming.HiZSetupTime = 252;

  if (HAL_NAND_Init(&hnand1, &ComSpaceTiming, &AttSpaceTiming) != HAL_OK)
  {
    Error_Handler( );
  }

  /** Perform the SDRAM1 memory initialization sequence
  */
  hsdram1.Instance = FMC_SDRAM_DEVICE;
  /* hsdram1.Init */
  hsdram1.Init.SDBank = FMC_SDRAM_BANK1;
  hsdram1.Init.ColumnBitsNumber = FMC_SDRAM_COLUMN_BITS_NUM_9;
  hsdram1.Init.RowBitsNumber = FMC_SDRAM_ROW_BITS_NUM_13;
  hsdram1.Init.MemoryDataWidth = FMC_SDRAM_MEM_BUS_WIDTH_16;
  hsdram1.Init.InternalBankNumber = FMC_SDRAM_INTERN_BANKS_NUM_4;
  hsdram1.Init.CASLatency = FMC_SDRAM_CAS_LATENCY_3;
  hsdram1.Init.WriteProtection = FMC_SDRAM_WRITE_PROTECTION_DISABLE;
  hsdram1.Init.SDClockPeriod = FMC_SDRAM_CLOCK_PERIOD_2;
  hsdram1.Init.ReadBurst = FMC_SDRAM_RBURST_DISABLE;
  hsdram1.Init.ReadPipeDelay = FMC_SDRAM_RPIPE_DELAY_1;
  /* SdramTiming */
  SdramTiming.LoadToActiveDelay = 2;
  SdramTiming.ExitSelfRefreshDelay = 8;
  SdramTiming.SelfRefreshTime = 5;
  SdramTiming.RowCycleDelay = 8;
  SdramTiming.WriteRecoveryTime = 4;
  SdramTiming.RPDelay = 2;
  SdramTiming.RCDDelay = 2;

  if (HAL_SDRAM_Init(&hsdram1, &SdramTiming) != HAL_OK)
  {
    Error_Handler( );
  }

}

static void MX_GPIO_Init(void)
{
  GPIO_InitTypeDef GPIO_InitStruct = {0};

  /* GPIO Ports Clock Enable */
  __HAL_RCC_GPIOE_CLK_ENABLE();
  __HAL_RCC_GPIOC_CLK_ENABLE();
  __HAL_RCC_GPIOI_CLK_ENABLE();
  __HAL_RCC_GPIOF_CLK_ENABLE();
  __HAL_RCC_GPIOH_CLK_ENABLE();
  __HAL_RCC_GPIOA_CLK_ENABLE();
  __HAL_RCC_GPIOB_CLK_ENABLE();
  __HAL_RCC_GPIOJ_CLK_ENABLE();
  __HAL_RCC_GPIOG_CLK_ENABLE();
  __HAL_RCC_GPIOD_CLK_ENABLE();
  __HAL_RCC_GPIOK_CLK_ENABLE();

  /*Configure GPIO pin Output Level */
  HAL_GPIO_WritePin(GPIOI, COMM2_Pin|COMM1_Pin, GPIO_PIN_SET);

  /*Configure GPIO pin Output Level */
  HAL_GPIO_WritePin(G4_PWR_GPIO_Port, G4_PWR_Pin, GPIO_PIN_RESET);

  /*Configure GPIO pin Output Level */
  HAL_GPIO_WritePin(BEEP_GPIO_Port, BEEP_Pin, GPIO_PIN_RESET);

  /*Configure GPIO pin Output Level */
  HAL_GPIO_WritePin(SPI3_NSS_GPIO_Port, SPI3_NSS_Pin, GPIO_PIN_SET);

  /*Configure GPIO pin Output Level */
  HAL_GPIO_WritePin(GPIOB, SPI2_NSS_Pin|TC_SCL_Pin|TC_SDA_Pin, GPIO_PIN_SET);

  /*Configure GPIO pin Output Level */
  HAL_GPIO_WritePin(W5500_RST_GPIO_Port, W5500_RST_Pin, GPIO_PIN_SET);

  /*Configure GPIO pin Output Level */
  HAL_GPIO_WritePin(AD_RESET_GPIO_Port, AD_RESET_Pin, GPIO_PIN_RESET);

  /*Configure GPIO pin Output Level */
  HAL_GPIO_WritePin(GPIOG, GPIO_PIN_10, GPIO_PIN_SET);

  /*Configure GPIO pins : COMM2_Pin COMM1_Pin */
  GPIO_InitStruct.Pin = COMM2_Pin|COMM1_Pin;
  GPIO_InitStruct.Mode = GPIO_MODE_OUTPUT_OD;
  GPIO_InitStruct.Pull = GPIO_PULLUP;
  GPIO_InitStruct.Speed = GPIO_SPEED_FREQ_VERY_HIGH;
  HAL_GPIO_Init(GPIOI, &GPIO_InitStruct);

  /*Configure GPIO pin : G4_PWR_Pin */
  GPIO_InitStruct.Pin = G4_PWR_Pin;
  GPIO_InitStruct.Mode = GPIO_MODE_OUTPUT_PP;
  GPIO_InitStruct.Pull = GPIO_NOPULL;
  GPIO_InitStruct.Speed = GPIO_SPEED_FREQ_LOW;
  HAL_GPIO_Init(G4_PWR_GPIO_Port, &GPIO_InitStruct);

  /*Configure GPIO pin : BEEP_Pin */
  GPIO_InitStruct.Pin = BEEP_Pin;
  GPIO_InitStruct.Mode = GPIO_MODE_OUTPUT_PP;
  GPIO_InitStruct.Pull = GPIO_NOPULL;
  GPIO_InitStruct.Speed = GPIO_SPEED_FREQ_VERY_HIGH;
  HAL_GPIO_Init(BEEP_GPIO_Port, &GPIO_InitStruct);

  /*Configure GPIO pin : HUM_DET_Pin */
  GPIO_InitStruct.Pin = HUM_DET_Pin;
  GPIO_InitStruct.Mode = GPIO_MODE_IT_RISING;
  GPIO_InitStruct.Pull = GPIO_NOPULL;
  HAL_GPIO_Init(HUM_DET_GPIO_Port, &GPIO_InitStruct);

  /*Configure GPIO pin : SPI3_NSS_Pin */
  GPIO_InitStruct.Pin = SPI3_NSS_Pin;
  GPIO_InitStruct.Mode = GPIO_MODE_OUTPUT_PP;
  GPIO_InitStruct.Pull = GPIO_NOPULL;
  GPIO_InitStruct.Speed = GPIO_SPEED_FREQ_VERY_HIGH;
  HAL_GPIO_Init(SPI3_NSS_GPIO_Port, &GPIO_InitStruct);

  /*Configure GPIO pin : PB1 */
  GPIO_InitStruct.Pin = GPIO_PIN_1;
  GPIO_InitStruct.Mode = GPIO_MODE_IT_FALLING;
  GPIO_InitStruct.Pull = GPIO_NOPULL;
  HAL_GPIO_Init(GPIOB, &GPIO_InitStruct);

  /*Configure GPIO pin : TC_INT_Pin */
  GPIO_InitStruct.Pin = TC_INT_Pin;
  GPIO_InitStruct.Mode = GPIO_MODE_IT_FALLING;
  GPIO_InitStruct.Pull = GPIO_NOPULL;
  HAL_GPIO_Init(TC_INT_GPIO_Port, &GPIO_InitStruct);

  /*Configure GPIO pin : SPI2_NSS_Pin */
  GPIO_InitStruct.Pin = SPI2_NSS_Pin;
  GPIO_InitStruct.Mode = GPIO_MODE_OUTPUT_PP;
  GPIO_InitStruct.Pull = GPIO_NOPULL;
  GPIO_InitStruct.Speed = GPIO_SPEED_FREQ_VERY_HIGH;
  HAL_GPIO_Init(SPI2_NSS_GPIO_Port, &GPIO_InitStruct);

  /*Configure GPIO pin : W5500_RST_Pin */
  GPIO_InitStruct.Pin = W5500_RST_Pin;
  GPIO_InitStruct.Mode = GPIO_MODE_OUTPUT_PP;
  GPIO_InitStruct.Pull = GPIO_NOPULL;
  GPIO_InitStruct.Speed = GPIO_SPEED_FREQ_VERY_HIGH;
  HAL_GPIO_Init(W5500_RST_GPIO_Port, &GPIO_InitStruct);

  /*Configure GPIO pin : W5500_INT_Pin */
  GPIO_InitStruct.Pin = W5500_INT_Pin;
  GPIO_InitStruct.Mode = GPIO_MODE_IT_FALLING;
  GPIO_InitStruct.Pull = GPIO_PULLUP;
  HAL_GPIO_Init(W5500_INT_GPIO_Port, &GPIO_InitStruct);

  /*Configure GPIO pins : AD_RESET_Pin PG10 */
  GPIO_InitStruct.Pin = AD_RESET_Pin|GPIO_PIN_10;
  GPIO_InitStruct.Mode = GPIO_MODE_OUTPUT_PP;
  GPIO_InitStruct.Pull = GPIO_NOPULL;
  GPIO_InitStruct.Speed = GPIO_SPEED_FREQ_VERY_HIGH;
  HAL_GPIO_Init(GPIOG, &GPIO_InitStruct);

  /*Configure GPIO pins : TC_SCL_Pin TC_SDA_Pin */
  GPIO_InitStruct.Pin = TC_SCL_Pin|TC_SDA_Pin;
  GPIO_InitStruct.Mode = GPIO_MODE_OUTPUT_OD;
  GPIO_InitStruct.Pull = GPIO_PULLUP;
  GPIO_InitStruct.Speed = GPIO_SPEED_FREQ_VERY_HIGH;
  HAL_GPIO_Init(GPIOB, &GPIO_InitStruct);

  /* EXTI interrupt init*/
  HAL_NVIC_SetPriority(EXTI1_IRQn, 0, 0);
  HAL_NVIC_EnableIRQ(EXTI1_IRQn);

  HAL_NVIC_SetPriority(EXTI9_5_IRQn, 0, 0);
  HAL_NVIC_EnableIRQ(EXTI9_5_IRQn);

}

void Error_Handler(void)
{
  __disable_irq();
  while (1)
  {
  }
}
